VERSION 5.7 ;
  NOWIREEXTENSIONATPIN ON ;
  DIVIDERCHAR "/" ;
  BUSBITCHARS "[]" ;
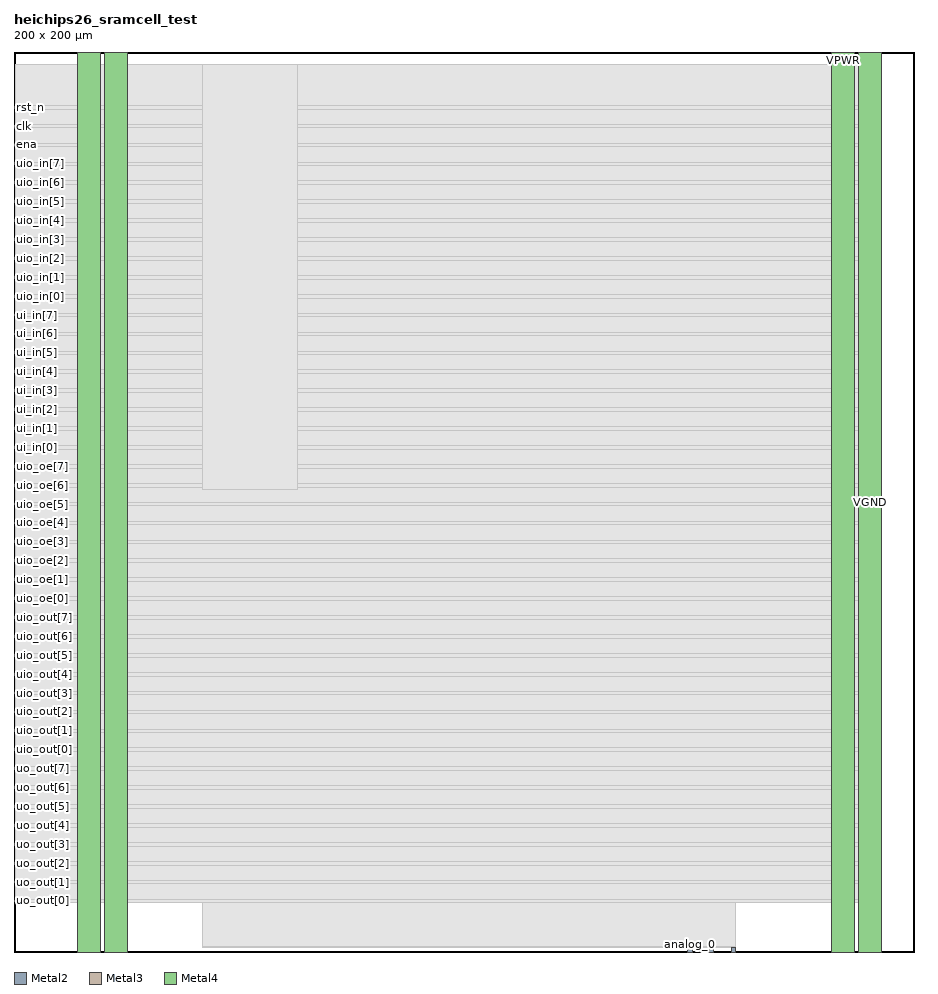
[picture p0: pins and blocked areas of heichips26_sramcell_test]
MACRO heichips26_sramcell_test
  CLASS BLOCK ;
  FOREIGN heichips26_sramcell_test ;
  ORIGIN 0.000 0.000 ;
  SIZE 200.000 BY 200.000 ;
  PIN analog_0
    DIRECTION INOUT ;
    USE SIGNAL ;
    ANTENNAGATEAREA 0.045500 ;
    ANTENNADIFFAREA 0.176750 ;
    PORT
      LAYER Metal2 ;
        RECT 149.740 0.000 150.740 1.000 ;
    END
  END analog_0
  PIN analog_1
    DIRECTION INOUT ;
    USE SIGNAL ;
    ANTENNAGATEAREA 0.045500 ;
    ANTENNADIFFAREA 0.176750 ;
    PORT
      LAYER Metal2 ;
        RECT 154.540 0.000 155.540 1.000 ;
    END
  END analog_1
  PIN analog_2
    DIRECTION INOUT ;
    USE SIGNAL ;
    ANTENNAGATEAREA 0.045500 ;
    ANTENNADIFFAREA 0.176750 ;
    PORT
      LAYER Metal2 ;
        RECT 159.340 0.000 160.340 1.000 ;
    END
  END analog_2
  PIN clk
    DIRECTION INPUT ;
    USE SIGNAL ;
    PORT
      LAYER Metal3 ;
        RECT 0.000 183.340 0.400 183.740 ;
    END
  END clk
  PIN ena
    DIRECTION INPUT ;
    USE SIGNAL ;
    PORT
      LAYER Metal3 ;
        RECT 0.000 179.140 0.400 179.540 ;
    END
  END ena
  PIN rst_n
    DIRECTION INPUT ;
    USE SIGNAL ;
    PORT
      LAYER Metal3 ;
        RECT 0.000 187.540 0.400 187.940 ;
    END
  END rst_n
  PIN ui_in[0]
    DIRECTION INPUT ;
    USE SIGNAL ;
    ANTENNAGATEAREA 0.180700 ;
    PORT
      LAYER Metal3 ;
        RECT 0.000 111.940 0.400 112.340 ;
    END
  END ui_in[0]
  PIN ui_in[1]
    DIRECTION INPUT ;
    USE SIGNAL ;
    ANTENNAGATEAREA 0.180700 ;
    PORT
      LAYER Metal3 ;
        RECT 0.000 116.140 0.400 116.540 ;
    END
  END ui_in[1]
  PIN ui_in[2]
    DIRECTION INPUT ;
    USE SIGNAL ;
    ANTENNAGATEAREA 0.180700 ;
    PORT
      LAYER Metal3 ;
        RECT 0.000 120.340 0.400 120.740 ;
    END
  END ui_in[2]
  PIN ui_in[3]
    DIRECTION INPUT ;
    USE SIGNAL ;
    ANTENNAGATEAREA 0.180700 ;
    PORT
      LAYER Metal3 ;
        RECT 0.000 124.540 0.400 124.940 ;
    END
  END ui_in[3]
  PIN ui_in[4]
    DIRECTION INPUT ;
    USE SIGNAL ;
    ANTENNAGATEAREA 0.180700 ;
    PORT
      LAYER Metal3 ;
        RECT 0.000 128.740 0.400 129.140 ;
    END
  END ui_in[4]
  PIN ui_in[5]
    DIRECTION INPUT ;
    USE SIGNAL ;
    ANTENNAGATEAREA 0.180700 ;
    PORT
      LAYER Metal3 ;
        RECT 0.000 132.940 0.400 133.340 ;
    END
  END ui_in[5]
  PIN ui_in[6]
    DIRECTION INPUT ;
    USE SIGNAL ;
    PORT
      LAYER Metal3 ;
        RECT 0.000 137.140 0.400 137.540 ;
    END
  END ui_in[6]
  PIN ui_in[7]
    DIRECTION INPUT ;
    USE SIGNAL ;
    PORT
      LAYER Metal3 ;
        RECT 0.000 141.340 0.400 141.740 ;
    END
  END ui_in[7]
  PIN uio_in[0]
    DIRECTION INPUT ;
    USE SIGNAL ;
    PORT
      LAYER Metal3 ;
        RECT 0.000 145.540 0.400 145.940 ;
    END
  END uio_in[0]
  PIN uio_in[1]
    DIRECTION INPUT ;
    USE SIGNAL ;
    PORT
      LAYER Metal3 ;
        RECT 0.000 149.740 0.400 150.140 ;
    END
  END uio_in[1]
  PIN uio_in[2]
    DIRECTION INPUT ;
    USE SIGNAL ;
    PORT
      LAYER Metal3 ;
        RECT 0.000 153.940 0.400 154.340 ;
    END
  END uio_in[2]
  PIN uio_in[3]
    DIRECTION INPUT ;
    USE SIGNAL ;
    PORT
      LAYER Metal3 ;
        RECT 0.000 158.140 0.400 158.540 ;
    END
  END uio_in[3]
  PIN uio_in[4]
    DIRECTION INPUT ;
    USE SIGNAL ;
    PORT
      LAYER Metal3 ;
        RECT 0.000 162.340 0.400 162.740 ;
    END
  END uio_in[4]
  PIN uio_in[5]
    DIRECTION INPUT ;
    USE SIGNAL ;
    PORT
      LAYER Metal3 ;
        RECT 0.000 166.540 0.400 166.940 ;
    END
  END uio_in[5]
  PIN uio_in[6]
    DIRECTION INPUT ;
    USE SIGNAL ;
    PORT
      LAYER Metal3 ;
        RECT 0.000 170.740 0.400 171.140 ;
    END
  END uio_in[6]
  PIN uio_in[7]
    DIRECTION INPUT ;
    USE SIGNAL ;
    PORT
      LAYER Metal3 ;
        RECT 0.000 174.940 0.400 175.340 ;
    END
  END uio_in[7]
  PIN uio_oe[0]
    DIRECTION OUTPUT ;
    USE SIGNAL ;
    PORT
      LAYER Metal3 ;
        RECT 0.000 78.340 0.400 78.740 ;
    END
  END uio_oe[0]
  PIN uio_oe[1]
    DIRECTION OUTPUT ;
    USE SIGNAL ;
    PORT
      LAYER Metal3 ;
        RECT 0.000 82.540 0.400 82.940 ;
    END
  END uio_oe[1]
  PIN uio_oe[2]
    DIRECTION OUTPUT ;
    USE SIGNAL ;
    PORT
      LAYER Metal3 ;
        RECT 0.000 86.740 0.400 87.140 ;
    END
  END uio_oe[2]
  PIN uio_oe[3]
    DIRECTION OUTPUT ;
    USE SIGNAL ;
    PORT
      LAYER Metal3 ;
        RECT 0.000 90.940 0.400 91.340 ;
    END
  END uio_oe[3]
  PIN uio_oe[4]
    DIRECTION OUTPUT ;
    USE SIGNAL ;
    PORT
      LAYER Metal3 ;
        RECT 0.000 95.140 0.400 95.540 ;
    END
  END uio_oe[4]
  PIN uio_oe[5]
    DIRECTION OUTPUT ;
    USE SIGNAL ;
    PORT
      LAYER Metal3 ;
        RECT 0.000 99.340 0.400 99.740 ;
    END
  END uio_oe[5]
  PIN uio_oe[6]
    DIRECTION OUTPUT ;
    USE SIGNAL ;
    PORT
      LAYER Metal3 ;
        RECT 0.000 103.540 0.400 103.940 ;
    END
  END uio_oe[6]
  PIN uio_oe[7]
    DIRECTION OUTPUT ;
    USE SIGNAL ;
    PORT
      LAYER Metal3 ;
        RECT 0.000 107.740 0.400 108.140 ;
    END
  END uio_oe[7]
  PIN uio_out[0]
    DIRECTION OUTPUT ;
    USE SIGNAL ;
    ANTENNAGATEAREA 0.045500 ;
    ANTENNADIFFAREA 0.176750 ;
    PORT
      LAYER Metal3 ;
        RECT 0.000 44.740 0.400 45.140 ;
    END
  END uio_out[0]
  PIN uio_out[1]
    DIRECTION OUTPUT ;
    USE SIGNAL ;
    ANTENNAGATEAREA 0.045500 ;
    ANTENNADIFFAREA 0.176750 ;
    PORT
      LAYER Metal3 ;
        RECT 0.000 48.940 0.400 49.340 ;
    END
  END uio_out[1]
  PIN uio_out[2]
    DIRECTION OUTPUT ;
    USE SIGNAL ;
    ANTENNAGATEAREA 0.045500 ;
    ANTENNADIFFAREA 0.176750 ;
    PORT
      LAYER Metal3 ;
        RECT 0.000 53.140 0.400 53.540 ;
    END
  END uio_out[2]
  PIN uio_out[3]
    DIRECTION OUTPUT ;
    USE SIGNAL ;
    ANTENNAGATEAREA 0.045500 ;
    ANTENNADIFFAREA 0.176750 ;
    PORT
      LAYER Metal3 ;
        RECT 0.000 57.340 0.400 57.740 ;
    END
  END uio_out[3]
  PIN uio_out[4]
    DIRECTION OUTPUT ;
    USE SIGNAL ;
    ANTENNAGATEAREA 0.045500 ;
    ANTENNADIFFAREA 0.176750 ;
    PORT
      LAYER Metal3 ;
        RECT 0.000 61.540 0.400 61.940 ;
    END
  END uio_out[4]
  PIN uio_out[5]
    DIRECTION OUTPUT ;
    USE SIGNAL ;
    ANTENNAGATEAREA 0.045500 ;
    ANTENNADIFFAREA 0.176750 ;
    PORT
      LAYER Metal3 ;
        RECT 0.000 65.740 0.400 66.140 ;
    END
  END uio_out[5]
  PIN uio_out[6]
    DIRECTION OUTPUT ;
    USE SIGNAL ;
    ANTENNAGATEAREA 0.045500 ;
    ANTENNADIFFAREA 0.176750 ;
    PORT
      LAYER Metal3 ;
        RECT 0.000 69.940 0.400 70.340 ;
    END
  END uio_out[6]
  PIN uio_out[7]
    DIRECTION OUTPUT ;
    USE SIGNAL ;
    ANTENNAGATEAREA 0.045500 ;
    ANTENNADIFFAREA 0.176750 ;
    PORT
      LAYER Metal3 ;
        RECT 0.000 74.140 0.400 74.540 ;
    END
  END uio_out[7]
  PIN uo_out[0]
    DIRECTION OUTPUT ;
    USE SIGNAL ;
    ANTENNAGATEAREA 0.045500 ;
    ANTENNADIFFAREA 0.176750 ;
    PORT
      LAYER Metal3 ;
        RECT 0.000 11.140 0.400 11.540 ;
    END
  END uo_out[0]
  PIN uo_out[1]
    DIRECTION OUTPUT ;
    USE SIGNAL ;
    ANTENNAGATEAREA 0.045500 ;
    ANTENNADIFFAREA 0.176750 ;
    PORT
      LAYER Metal3 ;
        RECT 0.000 15.340 0.400 15.740 ;
    END
  END uo_out[1]
  PIN uo_out[2]
    DIRECTION OUTPUT ;
    USE SIGNAL ;
    ANTENNAGATEAREA 0.045500 ;
    ANTENNADIFFAREA 0.176750 ;
    PORT
      LAYER Metal3 ;
        RECT 0.000 19.540 0.400 19.940 ;
    END
  END uo_out[2]
  PIN uo_out[3]
    DIRECTION OUTPUT ;
    USE SIGNAL ;
    ANTENNAGATEAREA 0.045500 ;
    ANTENNADIFFAREA 0.176750 ;
    PORT
      LAYER Metal3 ;
        RECT 0.000 23.740 0.400 24.140 ;
    END
  END uo_out[3]
  PIN uo_out[4]
    DIRECTION OUTPUT ;
    USE SIGNAL ;
    ANTENNAGATEAREA 0.045500 ;
    ANTENNADIFFAREA 0.176750 ;
    PORT
      LAYER Metal3 ;
        RECT 0.000 27.940 0.400 28.340 ;
    END
  END uo_out[4]
  PIN uo_out[5]
    DIRECTION OUTPUT ;
    USE SIGNAL ;
    ANTENNAGATEAREA 0.045500 ;
    ANTENNADIFFAREA 0.176750 ;
    PORT
      LAYER Metal3 ;
        RECT 0.000 32.140 0.400 32.540 ;
    END
  END uo_out[5]
  PIN uo_out[6]
    DIRECTION OUTPUT ;
    USE SIGNAL ;
    ANTENNAGATEAREA 0.045500 ;
    ANTENNADIFFAREA 0.176750 ;
    PORT
      LAYER Metal3 ;
        RECT 0.000 36.340 0.400 36.740 ;
    END
  END uo_out[6]
  PIN uo_out[7]
    DIRECTION OUTPUT ;
    USE SIGNAL ;
    ANTENNAGATEAREA 0.045500 ;
    ANTENNADIFFAREA 0.176750 ;
    PORT
      LAYER Metal3 ;
        RECT 0.000 40.540 0.400 40.940 ;
    END
  END uo_out[7]
  PIN VGND
    DIRECTION INOUT ;
    USE GROUND ;
    PORT
      LAYER Metal4 ;
        RECT 187.750 0.000 192.750 200.000 ;
    END
    PORT
      LAYER Metal4 ;
        RECT 20.160 0.000 25.160 200.000 ;
    END
  END VGND
  PIN VPWR
    DIRECTION INOUT ;
    USE POWER ;
    PORT
      LAYER Metal4 ;
        RECT 181.750 0.000 186.750 200.000 ;
    END
    PORT
      LAYER Metal4 ;
        RECT 14.160 0.000 19.160 200.000 ;
    END
  END VPWR
  OBS
      LAYER GatPoly ;
        RECT 41.840 102.950 84.030 148.610 ;
      LAYER Metal1 ;
        RECT 41.840 102.880 84.030 148.680 ;
      LAYER Metal2 ;
        RECT 41.895 1.210 160.240 197.130 ;
        RECT 41.895 1.000 149.530 1.210 ;
        RECT 150.950 1.000 154.330 1.210 ;
        RECT 155.750 1.000 159.130 1.210 ;
      LAYER Metal3 ;
        RECT 0.400 188.150 192.745 197.130 ;
        RECT 0.610 187.330 192.745 188.150 ;
        RECT 0.400 183.950 192.745 187.330 ;
        RECT 0.610 183.130 192.745 183.950 ;
        RECT 0.400 179.750 192.745 183.130 ;
        RECT 0.610 178.930 192.745 179.750 ;
        RECT 0.400 175.550 192.745 178.930 ;
        RECT 0.610 174.730 192.745 175.550 ;
        RECT 0.400 171.350 192.745 174.730 ;
        RECT 0.610 170.530 192.745 171.350 ;
        RECT 0.400 167.150 192.745 170.530 ;
        RECT 0.610 166.330 192.745 167.150 ;
        RECT 0.400 162.950 192.745 166.330 ;
        RECT 0.610 162.130 192.745 162.950 ;
        RECT 0.400 158.750 192.745 162.130 ;
        RECT 0.610 157.930 192.745 158.750 ;
        RECT 0.400 154.550 192.745 157.930 ;
        RECT 0.610 153.730 192.745 154.550 ;
        RECT 0.400 150.350 192.745 153.730 ;
        RECT 0.610 149.530 192.745 150.350 ;
        RECT 0.400 146.150 192.745 149.530 ;
        RECT 0.610 145.330 192.745 146.150 ;
        RECT 0.400 141.950 192.745 145.330 ;
        RECT 0.610 141.130 192.745 141.950 ;
        RECT 0.400 137.750 192.745 141.130 ;
        RECT 0.610 136.930 192.745 137.750 ;
        RECT 0.400 133.550 192.745 136.930 ;
        RECT 0.610 132.730 192.745 133.550 ;
        RECT 0.400 129.350 192.745 132.730 ;
        RECT 0.610 128.530 192.745 129.350 ;
        RECT 0.400 125.150 192.745 128.530 ;
        RECT 0.610 124.330 192.745 125.150 ;
        RECT 0.400 120.950 192.745 124.330 ;
        RECT 0.610 120.130 192.745 120.950 ;
        RECT 0.400 116.750 192.745 120.130 ;
        RECT 0.610 115.930 192.745 116.750 ;
        RECT 0.400 112.550 192.745 115.930 ;
        RECT 0.610 111.730 192.745 112.550 ;
        RECT 0.400 108.350 192.745 111.730 ;
        RECT 0.610 107.530 192.745 108.350 ;
        RECT 0.400 104.150 192.745 107.530 ;
        RECT 0.610 103.330 192.745 104.150 ;
        RECT 0.400 99.950 192.745 103.330 ;
        RECT 0.610 99.130 192.745 99.950 ;
        RECT 0.400 95.750 192.745 99.130 ;
        RECT 0.610 94.930 192.745 95.750 ;
        RECT 0.400 91.550 192.745 94.930 ;
        RECT 0.610 90.730 192.745 91.550 ;
        RECT 0.400 87.350 192.745 90.730 ;
        RECT 0.610 86.530 192.745 87.350 ;
        RECT 0.400 83.150 192.745 86.530 ;
        RECT 0.610 82.330 192.745 83.150 ;
        RECT 0.400 78.950 192.745 82.330 ;
        RECT 0.610 78.130 192.745 78.950 ;
        RECT 0.400 74.750 192.745 78.130 ;
        RECT 0.610 73.930 192.745 74.750 ;
        RECT 0.400 70.550 192.745 73.930 ;
        RECT 0.610 69.730 192.745 70.550 ;
        RECT 0.400 66.350 192.745 69.730 ;
        RECT 0.610 65.530 192.745 66.350 ;
        RECT 0.400 62.150 192.745 65.530 ;
        RECT 0.610 61.330 192.745 62.150 ;
        RECT 0.400 57.950 192.745 61.330 ;
        RECT 0.610 57.130 192.745 57.950 ;
        RECT 0.400 53.750 192.745 57.130 ;
        RECT 0.610 52.930 192.745 53.750 ;
        RECT 0.400 49.550 192.745 52.930 ;
        RECT 0.610 48.730 192.745 49.550 ;
        RECT 0.400 45.350 192.745 48.730 ;
        RECT 0.610 44.530 192.745 45.350 ;
        RECT 0.400 41.150 192.745 44.530 ;
        RECT 0.610 40.330 192.745 41.150 ;
        RECT 0.400 36.950 192.745 40.330 ;
        RECT 0.610 36.130 192.745 36.950 ;
        RECT 0.400 32.750 192.745 36.130 ;
        RECT 0.610 31.930 192.745 32.750 ;
        RECT 0.400 28.550 192.745 31.930 ;
        RECT 0.610 27.730 192.745 28.550 ;
        RECT 0.400 24.350 192.745 27.730 ;
        RECT 0.610 23.530 192.745 24.350 ;
        RECT 0.400 20.150 192.745 23.530 ;
        RECT 0.610 19.330 192.745 20.150 ;
        RECT 0.400 15.950 192.745 19.330 ;
        RECT 0.610 15.130 192.745 15.950 ;
        RECT 0.400 11.750 192.745 15.130 ;
        RECT 0.610 11.035 192.745 11.750 ;
      LAYER Metal4 ;
        RECT 41.840 102.880 63.060 197.130 ;
  END
END heichips26_sramcell_test
END LIBRARY

